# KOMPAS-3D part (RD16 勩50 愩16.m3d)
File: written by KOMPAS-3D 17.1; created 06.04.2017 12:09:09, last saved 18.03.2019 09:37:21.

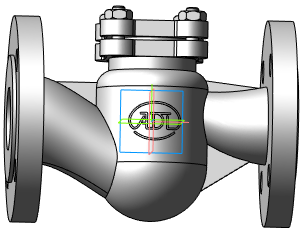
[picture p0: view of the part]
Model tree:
1. Операция без истории:2  (labels: Сталь 20  ГОСТ 1050-88)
